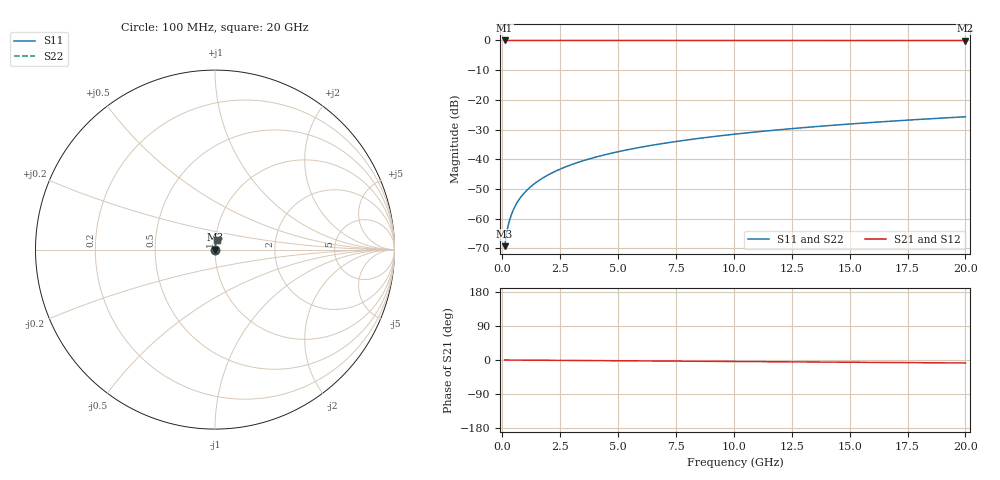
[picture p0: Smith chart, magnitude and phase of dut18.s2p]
! Touchstone file exported from HFSS 2026.1.0
!  File:  C:/ffzhzh/LocalFiles/Ansys_Project_Files/temp_test_TSV_18_1782978380_15332.aedt
!  Generated:  03:48:01 PM Jul  2, 2026
!  Design:  TSV
!  Project:  temp_test_TSV_18_1782978380_15332
! Variables:
!  h_bsmrdl = 2um
!  h_ox = 20um
!  h_rdl = 5um
!  h_sub = 67.82um
!  h_tmrdl = 5um
!  h_tsv = 67.82um
!  h_via = 3um
!  l_bsmrdl = 300um
!  l_sub = 414.9um
!  l_tmrdl = 200um
!  m_sub = 200um
!  pitch = 50.44um
!  r_tsv = 7.45um
!  s_tmrdl = 10um
!  w_bsmrdl = 18um
!  w_sub = 500um
!  w_tmrdl = 12um
!  x_tsv_center1 = 206um
!  x_tsv_center2 = 524um
!  x_tsv_center3 = 736um
!  x_tsv_center4 = 1054um
!  x_tsv_center5 = 1266um
!  x_tsv_center6 = 1584um
# GHz S MA R 50.000000
! Terminal data exported
! Port[1] = TSV1_1_T1
! Port[2] = TSV1_1_T2
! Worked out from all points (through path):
!   200 points, 100 MHz to 20 GHz, reference 50 ohm
!   highest |S21| = 0.00 dB at 100 MHz (marker M1); lowest = 0.0 dB at 20 GHz (marker M2)
!   group delay of S21, straight-line fit = 1.09 ps
!   lowest |S11| = -69.2 dB at 100 MHz (marker M3), VSWR 1.00, Z = 50 + j0.0298 ohm
!   |S11| at or under -10 dB: start of sweep to end of sweep
!   |S22| runs from -69.2 to -25.7 dB; largest |S21 - S12| = 2e-15
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0.1  0.0003457 59.6  0.9998 -0.0  0.9998 -0.0  0.0003457 59.6
! Gamma 0 0 0 0
! Port Impedance 50 0 50 0
0.2  0.0006226 72.8  0.9998 -0.1  0.9998 -0.1  0.0006226 72.8
0.3  0.0009099 77.4  0.9998 -0.1  0.9998 -0.1  0.0009099 77.4
0.4  0.001197 79.5  0.9998 -0.2  0.9998 -0.2  0.001197 79.5
0.5  0.001481 80.7  0.9998 -0.2  0.9998 -0.2  0.001481 80.7
0.6  0.001761 81.5  0.9997 -0.2  0.9997 -0.2  0.001761 81.5
0.7  0.002039 82.1  0.9997 -0.3  0.9997 -0.3  0.002039 82.1
0.8  0.002313 82.5  0.9997 -0.3  0.9997 -0.3  0.002313 82.5
1  0.002855 83.1  0.9997 -0.4  0.9997 -0.4  0.002855 83.1
1.4  0.003926 83.9  0.9996 -0.6  0.9996 -0.6  0.003926 83.9
1.7  0.004724 84.3  0.9996 -0.7  0.9996 -0.7  0.004724 84.3
2  0.00552 84.6  0.9995 -0.8  0.9995 -0.8  0.00552 84.6
2.7  0.007376 85.0  0.9995 -1.1  0.9995 -1.1  0.007376 85.0
3.5  0.00949 85.2  0.9994 -1.4  0.9994 -1.4  0.00949 85.2
4.2  0.01133 85.2  0.9993 -1.7  0.9993 -1.7  0.01133 85.2
5  0.01343 85.1  0.9992 -2.0  0.9992 -2.0  0.01343 85.1
6.8  0.01812 84.8  0.999 -2.7  0.999 -2.7  0.01812 84.8
8.3  0.02201 84.4  0.9989 -3.3  0.9989 -3.3  0.02201 84.4
10.1  0.02667 84.0  0.9987 -4.0  0.9987 -4.0  0.02667 84.0
13.4  0.03516 82.9  0.9983 -5.3  0.9983 -5.3  0.03516 82.9
16.7  0.04361 81.8  0.9978 -6.6  0.9978 -6.6  0.04361 81.8
20  0.052 80.7  0.9973 -7.9  0.9973 -7.9  0.052 80.7
